VERSION 5.7 ;
  NOWIREEXTENSIONATPIN ON ;
  DIVIDERCHAR "/" ;
  BUSBITCHARS "[]" ;
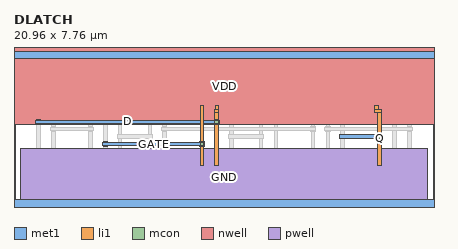
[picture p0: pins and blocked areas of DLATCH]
MACRO DLATCH
  CLASS CORE ;
  FOREIGN DLATCH ;
  ORIGIN 0.000 0.000 ;
  SIZE 20.960 BY 7.760 ;
  SYMMETRY X Y ;
  SITE unitrh ;
  PIN Q
    DIRECTION OUTPUT ;
    USE SIGNAL ;
    ANTENNAGATEAREA 1.027250 ;
    ANTENNADIFFAREA 0.963050 ;
    PORT
      LAYER met1 ;
        RECT 16.285 3.595 16.515 3.625 ;
        RECT 18.135 3.595 18.365 3.625 ;
        RECT 16.255 3.425 18.395 3.595 ;
        RECT 16.285 3.395 16.515 3.425 ;
        RECT 18.135 3.395 18.365 3.425 ;
    END
    PORT
      LAYER li1 ;
        RECT 18.010 4.890 18.180 5.050 ;
        RECT 18.010 4.720 18.335 4.890 ;
        RECT 18.165 2.095 18.335 4.720 ;
      LAYER mcon ;
        RECT 18.165 3.425 18.335 3.595 ;
    END
  END Q
  PIN D
    DIRECTION INPUT ;
    USE SIGNAL ;
    ANTENNAGATEAREA 2.054500 ;
    PORT
      LAYER met1 ;
        RECT 1.115 4.335 1.345 4.365 ;
        RECT 9.995 4.335 10.225 4.365 ;
        RECT 1.085 4.165 10.255 4.335 ;
        RECT 1.115 4.135 1.345 4.165 ;
        RECT 9.995 4.135 10.225 4.165 ;
    END
    PORT
      LAYER li1 ;
        RECT 10.055 4.890 10.225 5.045 ;
        RECT 10.025 4.715 10.225 4.890 ;
        RECT 10.025 2.095 10.195 4.715 ;
      LAYER mcon ;
        RECT 10.025 4.165 10.195 4.335 ;
    END
  END D
  PIN GATE
    DIRECTION INPUT ;
    USE SIGNAL ;
    ANTENNAGATEAREA 2.060500 ;
    PORT
      LAYER met1 ;
        RECT 4.445 3.225 4.675 3.255 ;
        RECT 9.255 3.225 9.485 3.255 ;
        RECT 4.415 3.055 9.515 3.225 ;
        RECT 4.445 3.025 4.675 3.055 ;
        RECT 9.255 3.025 9.485 3.055 ;
    END
    PORT
      LAYER li1 ;
        RECT 9.285 2.095 9.455 5.045 ;
      LAYER mcon ;
        RECT 9.285 3.055 9.455 3.225 ;
    END
  END GATE
  PIN VDD
    DIRECTION INOUT ;
    USE POWER ;
    SHAPE ABUTMENT ;
    PORT
      LAYER nwell ;
        RECT 0.000 4.110 20.960 7.940 ;
      LAYER met1 ;
        RECT 0.000 7.410 20.960 7.760 ;
    END
  END VDD
  PIN GND
    DIRECTION INOUT ;
    USE GROUND ;
    SHAPE ABUTMENT ;
    PORT
      LAYER pwell ;
        RECT 0.320 0.000 20.640 2.900 ;
      LAYER met1 ;
        RECT 0.000 0.000 20.960 0.350 ;
    END
  END GND
  OBS
      LAYER li1 ;
        RECT 0.000 7.410 20.960 7.760 ;
        RECT 0.320 4.290 0.660 7.410 ;
        RECT 1.080 5.365 1.250 7.410 ;
        RECT 0.320 0.350 0.660 2.900 ;
        RECT 1.145 2.100 1.315 5.045 ;
        RECT 1.520 4.845 1.690 7.200 ;
        RECT 1.960 5.365 2.130 7.410 ;
        RECT 1.520 4.675 2.055 4.845 ;
        RECT 1.885 2.345 2.055 4.675 ;
        RECT 2.540 4.290 2.880 7.410 ;
        RECT 3.415 5.315 3.585 7.410 ;
        RECT 3.855 5.465 4.025 7.200 ;
        RECT 4.295 5.735 4.465 7.410 ;
        RECT 4.735 5.465 4.905 7.200 ;
        RECT 5.175 5.735 5.345 7.410 ;
        RECT 3.855 5.295 5.385 5.465 ;
        RECT 1.515 2.175 2.055 2.345 ;
        RECT 1.035 0.800 1.205 1.930 ;
        RECT 1.515 1.020 1.685 2.175 ;
        RECT 2.005 0.800 2.175 1.930 ;
        RECT 1.035 0.630 2.175 0.800 ;
        RECT 1.035 0.350 1.205 0.630 ;
        RECT 1.520 0.350 1.690 0.630 ;
        RECT 2.005 0.350 2.175 0.630 ;
        RECT 2.540 0.350 2.880 2.900 ;
        RECT 3.735 2.095 3.905 5.045 ;
        RECT 4.505 4.890 4.675 5.045 ;
        RECT 4.475 4.715 4.675 4.890 ;
        RECT 4.475 2.095 4.645 4.715 ;
        RECT 3.320 1.845 3.490 1.925 ;
        RECT 4.290 1.845 4.460 1.925 ;
        RECT 5.215 1.920 5.385 5.295 ;
        RECT 5.870 4.290 6.210 7.410 ;
        RECT 6.630 5.365 6.800 7.410 ;
        RECT 3.320 1.675 4.460 1.845 ;
        RECT 3.320 0.545 3.490 1.675 ;
        RECT 3.805 0.350 3.975 1.300 ;
        RECT 4.290 0.795 4.460 1.675 ;
        RECT 4.775 1.750 5.385 1.920 ;
        RECT 4.775 1.015 4.945 1.750 ;
        RECT 5.260 0.795 5.430 1.565 ;
        RECT 4.290 0.625 5.430 0.795 ;
        RECT 4.290 0.545 4.460 0.625 ;
        RECT 5.260 0.545 5.430 0.625 ;
        RECT 5.870 0.350 6.210 2.900 ;
        RECT 6.695 2.100 6.865 5.045 ;
        RECT 7.070 4.845 7.240 7.200 ;
        RECT 7.510 5.365 7.680 7.410 ;
        RECT 7.070 4.675 7.605 4.845 ;
        RECT 7.435 2.345 7.605 4.675 ;
        RECT 8.090 4.290 8.430 7.410 ;
        RECT 8.965 5.315 9.135 7.410 ;
        RECT 9.405 5.465 9.575 7.200 ;
        RECT 9.845 5.735 10.015 7.410 ;
        RECT 10.285 5.465 10.455 7.200 ;
        RECT 10.725 5.735 10.895 7.410 ;
        RECT 9.405 5.295 10.935 5.465 ;
        RECT 7.065 2.175 7.605 2.345 ;
        RECT 6.585 0.800 6.755 1.930 ;
        RECT 7.065 1.020 7.235 2.175 ;
        RECT 7.555 0.800 7.725 1.930 ;
        RECT 6.585 0.630 7.725 0.800 ;
        RECT 6.585 0.350 6.755 0.630 ;
        RECT 7.070 0.350 7.240 0.630 ;
        RECT 7.555 0.350 7.725 0.630 ;
        RECT 8.090 0.350 8.430 2.900 ;
        RECT 8.870 1.845 9.040 1.925 ;
        RECT 9.840 1.845 10.010 1.925 ;
        RECT 10.765 1.920 10.935 5.295 ;
        RECT 11.420 4.290 11.760 7.410 ;
        RECT 12.180 5.365 12.350 7.410 ;
        RECT 8.870 1.675 10.010 1.845 ;
        RECT 8.870 0.545 9.040 1.675 ;
        RECT 9.355 0.350 9.525 1.300 ;
        RECT 9.840 0.795 10.010 1.675 ;
        RECT 10.325 1.750 10.935 1.920 ;
        RECT 10.325 1.015 10.495 1.750 ;
        RECT 10.810 0.795 10.980 1.565 ;
        RECT 9.840 0.625 10.980 0.795 ;
        RECT 9.840 0.545 10.010 0.625 ;
        RECT 10.810 0.545 10.980 0.625 ;
        RECT 11.420 0.350 11.760 2.900 ;
        RECT 12.245 2.100 12.415 5.045 ;
        RECT 12.620 4.845 12.790 7.200 ;
        RECT 13.060 5.365 13.230 7.410 ;
        RECT 12.620 4.675 13.155 4.845 ;
        RECT 12.985 2.345 13.155 4.675 ;
        RECT 13.640 4.290 13.980 7.410 ;
        RECT 14.515 5.475 14.685 7.205 ;
        RECT 14.955 5.735 15.125 7.410 ;
        RECT 15.395 7.005 16.445 7.175 ;
        RECT 15.395 5.475 15.565 7.005 ;
        RECT 14.515 5.305 15.565 5.475 ;
        RECT 15.835 5.475 16.005 6.745 ;
        RECT 16.275 5.735 16.445 7.005 ;
        RECT 15.835 5.305 16.485 5.475 ;
        RECT 14.680 4.890 14.850 5.050 ;
        RECT 15.610 4.890 15.780 5.050 ;
        RECT 14.680 4.720 15.005 4.890 ;
        RECT 12.615 2.175 13.155 2.345 ;
        RECT 12.135 0.800 12.305 1.930 ;
        RECT 12.615 1.020 12.785 2.175 ;
        RECT 13.105 0.800 13.275 1.930 ;
        RECT 12.135 0.630 13.275 0.800 ;
        RECT 12.135 0.350 12.305 0.630 ;
        RECT 12.620 0.350 12.790 0.630 ;
        RECT 13.105 0.350 13.275 0.630 ;
        RECT 13.640 0.350 13.980 2.900 ;
        RECT 14.835 2.095 15.005 4.720 ;
        RECT 15.575 4.720 15.780 4.890 ;
        RECT 15.575 2.095 15.745 4.720 ;
        RECT 14.420 0.795 14.590 1.925 ;
        RECT 16.315 1.920 16.485 5.305 ;
        RECT 16.970 4.290 17.310 7.410 ;
        RECT 17.845 5.475 18.015 7.205 ;
        RECT 18.285 5.735 18.455 7.410 ;
        RECT 18.725 7.005 19.775 7.175 ;
        RECT 18.725 5.475 18.895 7.005 ;
        RECT 17.845 5.305 18.895 5.475 ;
        RECT 19.165 5.475 19.335 6.745 ;
        RECT 19.605 5.735 19.775 7.005 ;
        RECT 19.165 5.305 19.815 5.475 ;
        RECT 18.940 4.890 19.110 5.050 ;
        RECT 18.905 4.720 19.110 4.890 ;
        RECT 14.905 1.750 16.485 1.920 ;
        RECT 14.905 1.015 15.075 1.750 ;
        RECT 15.390 0.795 15.560 1.570 ;
        RECT 15.875 1.015 16.045 1.750 ;
        RECT 16.360 0.795 16.530 1.570 ;
        RECT 14.420 0.625 16.530 0.795 ;
        RECT 14.420 0.350 14.590 0.625 ;
        RECT 14.905 0.350 15.075 0.625 ;
        RECT 15.390 0.350 15.560 0.625 ;
        RECT 15.875 0.350 16.045 0.625 ;
        RECT 16.360 0.350 16.530 0.625 ;
        RECT 16.970 0.350 17.310 2.900 ;
        RECT 18.905 2.095 19.075 4.720 ;
        RECT 17.750 0.795 17.920 1.925 ;
        RECT 19.645 1.920 19.815 5.305 ;
        RECT 20.300 4.290 20.640 7.410 ;
        RECT 18.235 1.750 19.815 1.920 ;
        RECT 18.235 1.015 18.405 1.750 ;
        RECT 18.720 0.795 18.890 1.570 ;
        RECT 19.205 1.015 19.375 1.750 ;
        RECT 19.690 0.795 19.860 1.570 ;
        RECT 17.750 0.625 19.860 0.795 ;
        RECT 17.750 0.350 17.920 0.625 ;
        RECT 18.235 0.350 18.405 0.625 ;
        RECT 18.720 0.350 18.890 0.625 ;
        RECT 19.205 0.350 19.375 0.625 ;
        RECT 19.690 0.350 19.860 0.625 ;
        RECT 20.300 0.350 20.640 2.900 ;
        RECT 0.000 0.000 20.960 0.350 ;
      LAYER mcon ;
        RECT 0.775 7.495 0.945 7.665 ;
        RECT 1.145 7.495 1.315 7.665 ;
        RECT 1.515 7.495 1.685 7.665 ;
        RECT 1.885 7.495 2.055 7.665 ;
        RECT 2.255 7.495 2.425 7.665 ;
        RECT 2.995 7.495 3.165 7.665 ;
        RECT 3.365 7.495 3.535 7.665 ;
        RECT 3.735 7.495 3.905 7.665 ;
        RECT 4.105 7.495 4.275 7.665 ;
        RECT 4.475 7.495 4.645 7.665 ;
        RECT 4.845 7.495 5.015 7.665 ;
        RECT 5.215 7.495 5.385 7.665 ;
        RECT 5.585 7.495 5.755 7.665 ;
        RECT 6.325 7.495 6.495 7.665 ;
        RECT 6.695 7.495 6.865 7.665 ;
        RECT 7.065 7.495 7.235 7.665 ;
        RECT 7.435 7.495 7.605 7.665 ;
        RECT 7.805 7.495 7.975 7.665 ;
        RECT 8.545 7.495 8.715 7.665 ;
        RECT 8.915 7.495 9.085 7.665 ;
        RECT 9.285 7.495 9.455 7.665 ;
        RECT 9.655 7.495 9.825 7.665 ;
        RECT 10.025 7.495 10.195 7.665 ;
        RECT 10.395 7.495 10.565 7.665 ;
        RECT 10.765 7.495 10.935 7.665 ;
        RECT 11.135 7.495 11.305 7.665 ;
        RECT 11.875 7.495 12.045 7.665 ;
        RECT 12.245 7.495 12.415 7.665 ;
        RECT 12.615 7.495 12.785 7.665 ;
        RECT 12.985 7.495 13.155 7.665 ;
        RECT 13.355 7.495 13.525 7.665 ;
        RECT 14.095 7.495 14.265 7.665 ;
        RECT 14.465 7.495 14.635 7.665 ;
        RECT 14.835 7.495 15.005 7.665 ;
        RECT 15.205 7.495 15.375 7.665 ;
        RECT 15.575 7.495 15.745 7.665 ;
        RECT 15.945 7.495 16.115 7.665 ;
        RECT 16.315 7.495 16.485 7.665 ;
        RECT 16.685 7.495 16.855 7.665 ;
        RECT 17.425 7.495 17.595 7.665 ;
        RECT 17.795 7.495 17.965 7.665 ;
        RECT 18.165 7.495 18.335 7.665 ;
        RECT 18.535 7.495 18.705 7.665 ;
        RECT 18.905 7.495 19.075 7.665 ;
        RECT 19.275 7.495 19.445 7.665 ;
        RECT 19.645 7.495 19.815 7.665 ;
        RECT 20.015 7.495 20.185 7.665 ;
        RECT 1.145 4.165 1.315 4.335 ;
        RECT 1.885 3.795 2.055 3.965 ;
        RECT 3.735 3.795 3.905 3.965 ;
        RECT 4.475 3.055 4.645 3.225 ;
        RECT 5.215 3.425 5.385 3.595 ;
        RECT 6.695 3.425 6.865 3.595 ;
        RECT 7.435 3.795 7.605 3.965 ;
        RECT 10.765 3.425 10.935 3.595 ;
        RECT 12.245 3.425 12.415 3.595 ;
        RECT 12.985 4.165 13.155 4.335 ;
        RECT 14.835 3.795 15.005 3.965 ;
        RECT 15.575 3.795 15.745 3.965 ;
        RECT 16.315 3.425 16.485 3.595 ;
        RECT 18.905 4.165 19.075 4.335 ;
        RECT 19.645 3.795 19.815 3.965 ;
        RECT 0.775 0.095 0.945 0.265 ;
        RECT 1.145 0.095 1.315 0.265 ;
        RECT 1.515 0.095 1.685 0.265 ;
        RECT 1.885 0.095 2.055 0.265 ;
        RECT 2.255 0.095 2.425 0.265 ;
        RECT 2.995 0.095 3.165 0.265 ;
        RECT 3.365 0.095 3.535 0.265 ;
        RECT 3.735 0.095 3.905 0.265 ;
        RECT 4.105 0.095 4.275 0.265 ;
        RECT 4.475 0.095 4.645 0.265 ;
        RECT 4.845 0.095 5.015 0.265 ;
        RECT 5.215 0.095 5.385 0.265 ;
        RECT 5.585 0.095 5.755 0.265 ;
        RECT 6.325 0.095 6.495 0.265 ;
        RECT 6.695 0.095 6.865 0.265 ;
        RECT 7.065 0.095 7.235 0.265 ;
        RECT 7.435 0.095 7.605 0.265 ;
        RECT 7.805 0.095 7.975 0.265 ;
        RECT 8.545 0.095 8.715 0.265 ;
        RECT 8.915 0.095 9.085 0.265 ;
        RECT 9.285 0.095 9.455 0.265 ;
        RECT 9.655 0.095 9.825 0.265 ;
        RECT 10.025 0.095 10.195 0.265 ;
        RECT 10.395 0.095 10.565 0.265 ;
        RECT 10.765 0.095 10.935 0.265 ;
        RECT 11.135 0.095 11.305 0.265 ;
        RECT 11.875 0.095 12.045 0.265 ;
        RECT 12.245 0.095 12.415 0.265 ;
        RECT 12.615 0.095 12.785 0.265 ;
        RECT 12.985 0.095 13.155 0.265 ;
        RECT 13.355 0.095 13.525 0.265 ;
        RECT 14.095 0.095 14.265 0.265 ;
        RECT 14.465 0.095 14.635 0.265 ;
        RECT 14.835 0.095 15.005 0.265 ;
        RECT 15.205 0.095 15.375 0.265 ;
        RECT 15.575 0.095 15.745 0.265 ;
        RECT 15.945 0.095 16.115 0.265 ;
        RECT 16.315 0.095 16.485 0.265 ;
        RECT 16.685 0.095 16.855 0.265 ;
        RECT 17.425 0.095 17.595 0.265 ;
        RECT 17.795 0.095 17.965 0.265 ;
        RECT 18.165 0.095 18.335 0.265 ;
        RECT 18.535 0.095 18.705 0.265 ;
        RECT 18.905 0.095 19.075 0.265 ;
        RECT 19.275 0.095 19.445 0.265 ;
        RECT 19.645 0.095 19.815 0.265 ;
        RECT 20.015 0.095 20.185 0.265 ;
      LAYER met1 ;
        RECT 12.955 4.335 13.185 4.365 ;
        RECT 18.875 4.335 19.105 4.365 ;
        RECT 12.925 4.165 19.135 4.335 ;
        RECT 12.955 4.135 13.185 4.165 ;
        RECT 18.875 4.135 19.105 4.165 ;
        RECT 1.855 3.965 2.085 3.995 ;
        RECT 3.705 3.965 3.935 3.995 ;
        RECT 7.405 3.965 7.635 3.995 ;
        RECT 14.805 3.965 15.035 3.995 ;
        RECT 15.545 3.965 15.775 3.995 ;
        RECT 19.615 3.965 19.845 3.995 ;
        RECT 1.825 3.795 3.965 3.965 ;
        RECT 7.375 3.795 15.065 3.965 ;
        RECT 15.515 3.795 19.875 3.965 ;
        RECT 1.855 3.765 2.085 3.795 ;
        RECT 3.705 3.765 3.935 3.795 ;
        RECT 7.405 3.765 7.635 3.795 ;
        RECT 14.805 3.765 15.035 3.795 ;
        RECT 15.545 3.765 15.775 3.795 ;
        RECT 19.615 3.765 19.845 3.795 ;
        RECT 5.185 3.595 5.415 3.625 ;
        RECT 6.665 3.595 6.895 3.625 ;
        RECT 10.735 3.595 10.965 3.625 ;
        RECT 12.215 3.595 12.445 3.625 ;
        RECT 5.155 3.425 6.925 3.595 ;
        RECT 10.705 3.425 12.475 3.595 ;
        RECT 5.185 3.395 5.415 3.425 ;
        RECT 6.665 3.395 6.895 3.425 ;
        RECT 10.735 3.395 10.965 3.425 ;
        RECT 12.215 3.395 12.445 3.425 ;
  END
END DLATCH
END LIBRARY

